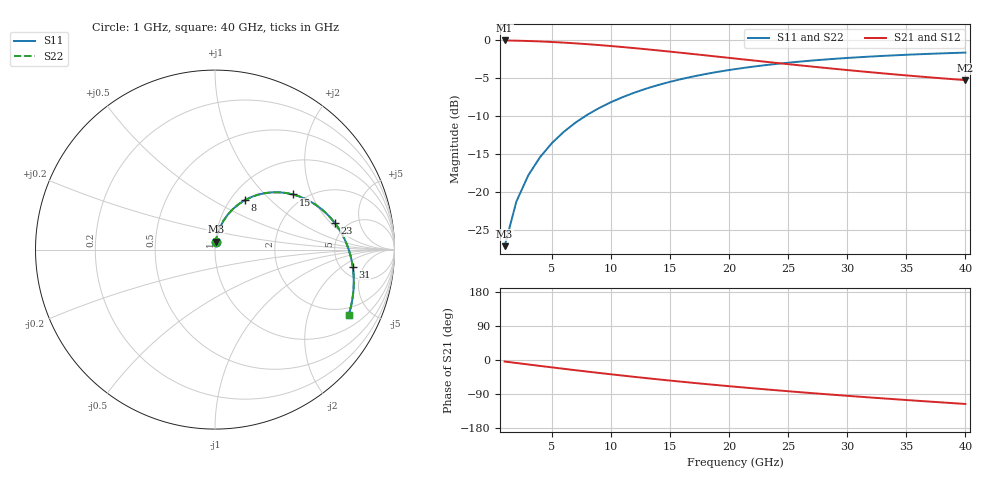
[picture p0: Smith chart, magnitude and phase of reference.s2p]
! circuitRF F0 spike reference -- case A, Palace, round wire (conductivity boundary)
! Palace postpro/port-S.csv, dB/deg -> RI; port 1 excited only; S22 = S11 and S12 = S21 by the mirror symmetry of the geometry about x = 0
# GHz S RI R 50
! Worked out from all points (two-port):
!   40 points, 1 GHz to 40 GHz, reference 50 ohm
!   highest |S21| = -0.02 dB at 1 GHz (marker M1); lowest = -5.3 dB at 40 GHz (marker M2)
!   |S21| within 3 dB of the highest: start of sweep to 24.22 GHz
!   lowest |S11| = -27.2 dB at 1 GHz (marker M3), VSWR 1.09, Z = 50.2 + j4.38 ohm
!   |S11| at or under -10 dB: start of sweep to 7.842 GHz
!   |S22| runs from -27.2 to -1.6 dB; largest |S21 - S12| = 0
!   S11 on the Smith chart (normalised r, x): 1 GHz: 1.00, +0.09; 8 GHz: 1.16, +0.72; 15 GHz: 1.73, +1.48; 23 GHz: 4.04, +2.24; 31 GHz: 6.38, -3.00; 40 GHz: 1.56, -3.67
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1  0.00437 0.0435  0.9953 -0.0692  0.9953 -0.0692  0.00437 0.0435
2  0.0137 0.0852  0.9849 -0.1365  0.9849 -0.1365  0.0137 0.0852
3  0.0284 0.125  0.9686 -0.202  0.9686 -0.202  0.0284 0.125
4  0.0482 0.1623  0.9465 -0.2649  0.9465 -0.2649  0.0482 0.1623
5  0.0724 0.1965  0.9192 -0.3246  0.9192 -0.3246  0.0724 0.1965
6  0.1008 0.227  0.8872 -0.3806  0.8872 -0.3806  0.1008 0.227
7  0.1325 0.2535  0.8512 -0.4324  0.8512 -0.4324  0.1325 0.2535
8  0.1669 0.2757  0.8117 -0.4798  0.8117 -0.4798  0.1669 0.2757
9  0.2035 0.2933  0.7695 -0.5225  0.7695 -0.5225  0.2035 0.2933
11  0.2804 0.315  0.6794 -0.594  0.6794 -0.594  0.2804 0.315
12  0.3195 0.3192  0.6327 -0.6227  0.6327 -0.6227  0.3195 0.3192
14  0.3968 0.3152  0.5383 -0.6672  0.5383 -0.6672  0.3968 0.3152
15  0.4341 0.3074  0.4916 -0.6835  0.4916 -0.6835  0.4341 0.3074
18  0.5369 0.2649  0.3566 -0.7112  0.3566 -0.7112  0.5369 0.2649
21  0.6222 0.1997  0.2336 -0.7137  0.2336 -0.7137  0.6222 0.1997
23  0.6683 0.1474  0.1595 -0.7049  0.1595 -0.7049  0.6683 0.1474
25  0.7055 0.0904  0.092 -0.6899  0.092 -0.6899  0.7055 0.0904
27  0.7342 0.0302  0.0308 -0.6701  0.0308 -0.6701  0.7342 0.0302
31  0.7674 -0.0946  -0.0738 -0.6211  -0.0738 -0.6211  0.7674 -0.0946
34  0.7733 -0.1883  -0.1385 -0.5793  -0.1385 -0.5793  0.7733 -0.1883
37  0.7649 -0.2795  -0.1931 -0.5354  -0.1931 -0.5354  0.7649 -0.2795
40  0.7441 -0.3665  -0.2392 -0.4906  -0.2392 -0.4906  0.7441 -0.3665
